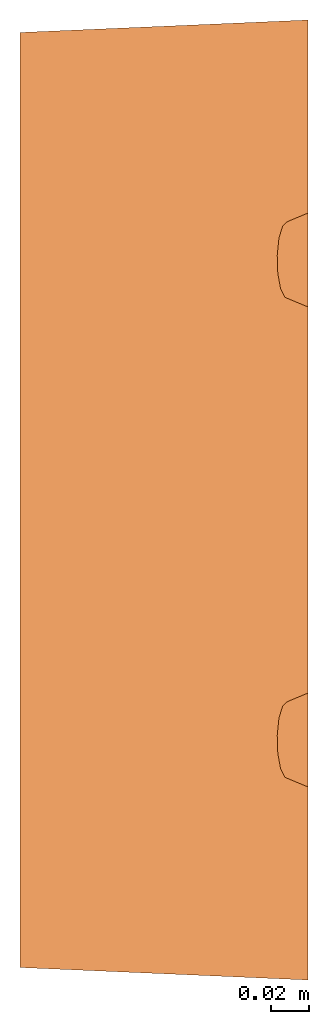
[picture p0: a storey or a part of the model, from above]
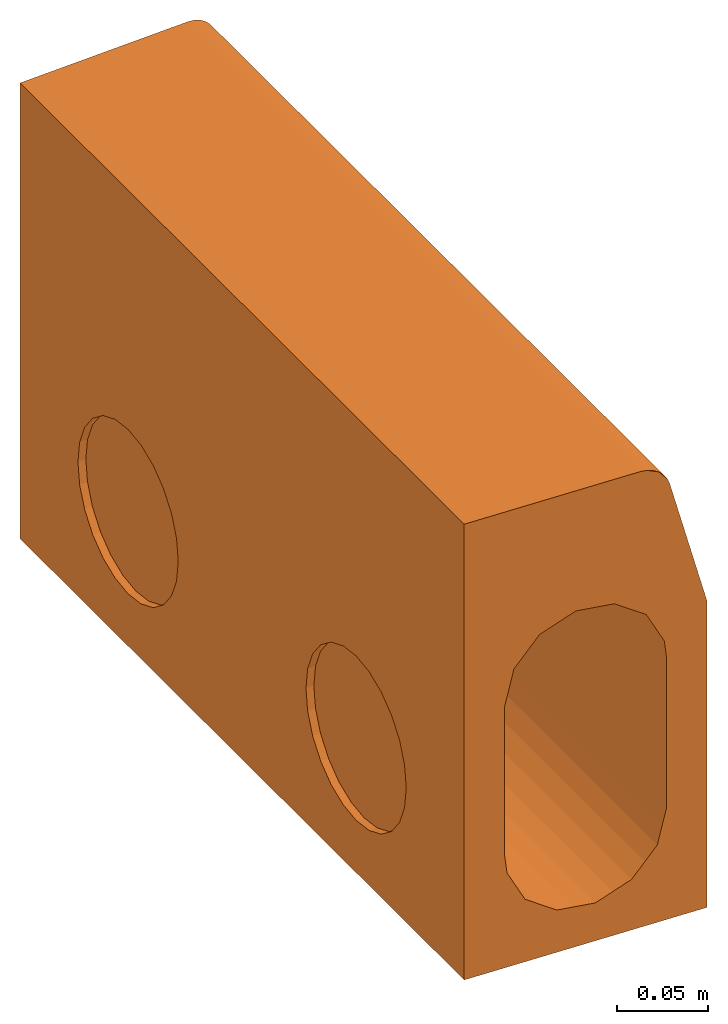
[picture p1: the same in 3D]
Properties of the parts of a building model (IFC2X3)

# File
Description: ViewDefinition [CoordinationView]
File name: 7968 - 7-6m external mitre.ifc
Time: 2013-09-12T12:55:43
Written by: Autodesk Revit 2013
Made in: 20120221_2030(x64)

# IfcProject, Project Number
LongName: Project Name; Phase: Project Status

# IfcSite, Default
RefLatitude: 42, 21, 30, 344238; RefLongitude: -71, -3, -35, -194702; RefElevation: 0 mm

# IfcBuilding
Pset_BuildingCommon - NumberOfStoreys: 2
Other - Project Name: Project Name; Project Status: Project Status; Project Number: Project Number; Project Issue Date: Issue Date; Project Address: Enter address here; Client Name: Owner

# IfcBuildingStorey (2)
Constraints - Elevation Base: 0
Graphics - Line Pattern: Center; Color: 0; Symbol at End 2 Default: yes; Line Weight: 1; Symbol: M_Level Head - Circle: M_Level Head - Circle; Symbol at End 1 Default: no
Identity Data - Building Story: yes; Structural: no
Dimensions - Computation Height: 0 mm
Name | LongName = Name | Elevation (mm) = Constraints, Elevation (mm)
T.O. Fnd. Wall | T.O. Fnd. Wall | -300
Level 1 | Level 1 | 0

# IfcBuildingElementProxy: 7968 - 7-6m external mitre, Civil-Drainage-Channel-ACO-KerbDrain-HB305 Part 2:7968 - 7-6m external mitre:7968 - 7-6m external mitre:263456
In: T.O. Fnd. Wall
Material: ACO Polymer Concrete.
General - TagNumber: 0.000000; SerialNumber: 0.000000
Materials and Finishes - End Cap Colour: N/A; Access Cover/Frame Finish: N/A; Connection Pipe Material: N/A; End Cap Material: N/A; Access Cover/Frame Colour: N/A; Connection Pipe Material Colour: N/A; Channel Colour: Grey; Channel Material: Vienite® Synthetic Resin Concrete; Access Cover/Frame Material: N/A
Dimensions - Volume: 12638493 mm3; Curved RH Void End: -3070 mm; 1.8m Radius Unit void End: -4805 mm; Curved RH Void Start: -3060 mm; Void_Length: 500 mm; Curved LH Void Start: 3000 mm; Flush Drainable Centre Stone Void End: -4505 mm; Void_Width: 150 mm; Quadrant void Start: 2600.7 mm; Void L Start: -3000 mm; Flush Drainable Centre Stone Void Start: -4500 mm; Mitre Void End: -180 mm; Mitre Void Start: 0 mm; 6m Radius unit void Start: -6000 mm; mitre small length: 484 mm; 6m Radius Unit Void end: -6005 mm; 1.8m Radius unit Void Start: -4800 mm; Mite Long Side Length: 497 mm; Curved LH Void End: 3010 mm; Quadrant void End: 2620 mm; Staright Void Depth: -5205 mm; Void L End: -3010 mm; Straight Void Depth: -5200 mm
Phasing - Phase Created: Phase 1
Constraints - Level: Level: Level 1; Moves With Nearby Elements: no
Pset_BuildingElementProxyCommon - Reference: 7968 - 7-6m external mitre
Green Building Properties - Channel Recyclable: Fully recyclable; End Cap Recycled Material Content: N/A; Channel Recycled Material Content: 20% minimum; Access Cover/Frame Recyclable: N/A; End Cap Recyclable: N/A; Access Cover/Frame Recycled Material Content: N/A
Construction - LH drop kerb- 6m ext rad: no; flush drainable centre stone: no; KDHB305 10-8m_external_mitre: no; KDHB305_quadrant: no; KDHB305 6m _external_radius: no; KDHB305 25-11m internal_mitre: no; KDHB305 1.8m_radius: no; KDHB305 internal_angle: no; KDHB305 25-11m external_mitre: no; KDHB305 7-6m external_mitre: yes; KDHB305 RH drop kerb-4999: no
Identity Data - Fax: +44 (0)1462 815895; e-mail Technical: technical@aco.co.uk; URL: www.aco.co.uk; Assembly Code: D2040; OmniClass Number: 23.70.50.24; Model: ACO KerbDrain HB305; Address: ACO Business Park, Hitchin Road, Shefford, Bedfordshire, United Kingdom SG17 5TE; Product Code: 7968; e-mail Sales: customersupport@aco.co.uk; Model Description: Combined kerb and drainage system; OmniClass Title: Rainwater Removal; Cost: 0; Telephone: +44 (0)1462 816666; Assembly Description: Rain Water Drainage; Price: POA - contact ACO; Type Comments: ACO KerbDrain HB305 half battered 7-6m external mitre unit 500/487mm long; Product Page URL: http://www.aco.co.uk/product_detail.php?id=3; Maintenance guidelines: http://www.aco.co.uk/download.php?id=120; Manufacturer: ACO Technologies plc - ACO Water Management Division; Installation guidelines: http://www.aco.co.uk/download.php?id=120; Product brochure: http://www.aco.co.uk/download.php?id=120
Data - Load Class: A 15 - D 400; Product Weight: 26.9 Kg; Product Dimensions: 500/487mm x 150mm x 305mm (LxWxH); Hydraulic Performance: http://www.aco.co.uk/download.php?id=120; ACO Hydraulic Design Software: http://www.acodesign.co.uk; Connection Pipe O.D: N/A; Drainage Slot Intake area: 14592mm²/m; Invert Depth: 280mm; Concrete Surround Volume - Load Class A 15 - D 400 - Grass or Asphalt Pavement: N/A; Concrete Surround Volume - Load Class A 15 - D 400 - Concrete Pavement: N/A; Product Standard: BS EN 1433:2002, CE marked, Kitemarked; Installation - Concrete Grade: Refer to brochure; Drainage Slot Width: 50mm; Channel C.S.A: 0.02m²
Other - Revision: 1; CreatedBy: www.aco.co.uk

# IfcOpeningElement: Recess (8)
In: Level 1
Structural - Enable Analytical Model: no; Structural: no
Phasing - Phase Created: Phase 1
Dimensions - Thickness: 400 mm; Volume: 11130326635 mm3; Area: 27858925 mm2; Perimeter: 21157.2 mm
Constraints - Related to Mass: no; Level: Level: Level 1; Height Offset From Level: 0 mm; Room Bounding: yes
Construction - Function: 0; Default Thickness: 400 mm
Analytical Properties - Absorptance: 0.1; Roughness: 1
Graphics - Coarse Scale Fill Color: 0

# IfcSlab: Floor:Generic Floor - 400mm, Floor:Generic Floor - 400mm:184025
In: Level 1
PredefinedType: FLOOR; Material: Default Floor 400 mm
Structural - Enable Analytical Model: no; Structural: no
Phasing - Phase Created: Phase 1
Dimensions - Thickness: 400 mm; Volume: 11130326635 mm3; Area: 27858925 mm2; Perimeter: 21157.2 mm
Constraints - Related to Mass: no; Level: Level: Level 1; Height Offset From Level: 0 mm; Room Bounding: yes
Pset_SlabCommon - Reference: Generic Floor - 400mm; IsExternal: no; LoadBearing: yes
Construction - Function: 0; Default Thickness: 400 mm
Analytical Properties - Absorptance: 0.1; Roughness: 1
Graphics - Coarse Scale Fill Color: 0
